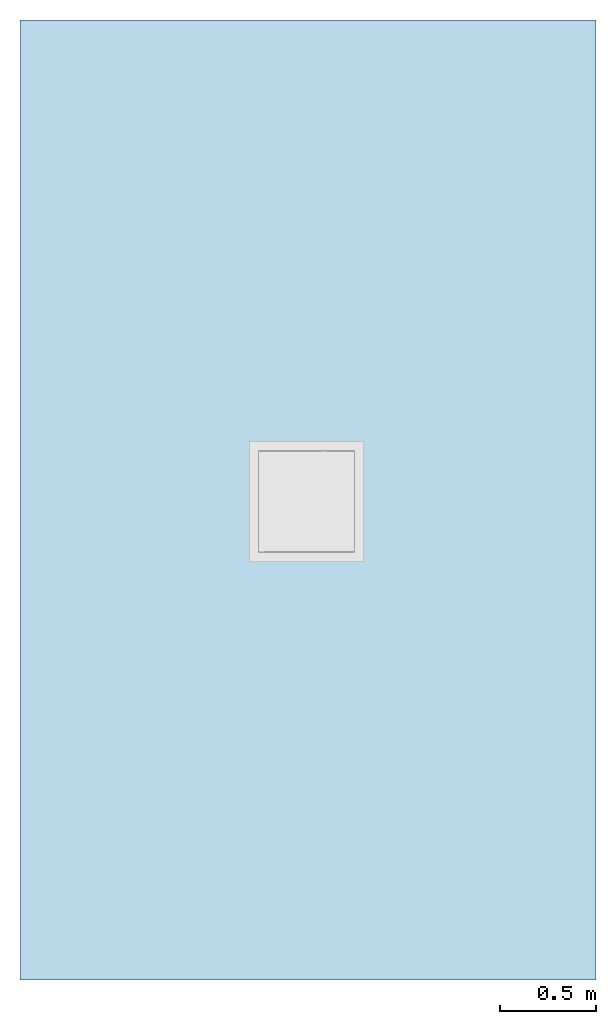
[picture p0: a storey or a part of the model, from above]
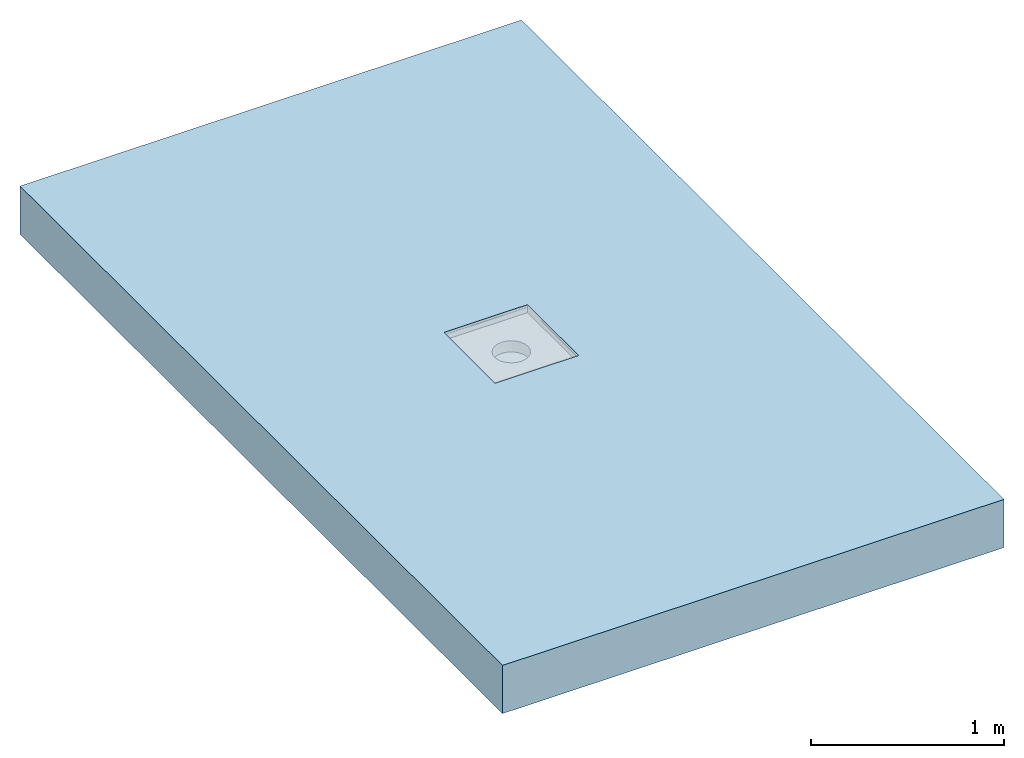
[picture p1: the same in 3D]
Properties of the parts of a building model (IFC2X3)

# File
Description: ViewDefinition [CoordinationView]
File name: Project Number
Time: 2016-11-22T10:02:17
Written by: The EXPRESS Data Manager Version 5.01.0100.02.64mod : 6 Jun 2012
Made in: 20130308_1515(x64) - Exporter 2014.0.2013.0308 - Default UI
Comment: STEP Physical File produced by: The EXPRESS Data Manager Version 5.01.0100.02.64mod : 6 Jun 2012 * Module: EDMstepFileFactory/EDMstandAlone * Creation date: Tue Nov 22 10:02:17 2016 * Host: IN-BLR-PC-0012 * Database: C:\Users\pakumar\AppData\Local\Temp\{4FF520C0-FC0E-452F-8ADC-81A6F5B29089}\ifc * Database version: 5507 * Database creation date: Tue Nov 22 10:02:16 2016 * Schema: IFC2X3 * Model: DataRepository.ifc * Model creation date: Tue Nov 22 10:02:16 2016 * Header model: DataRepository.ifc_HeaderModel * Header model creation date: Tue Nov 22 10:02:16 2016 * EDMuser: sdai-user * EDMgroup: sdai-group * License ID and type: 5605 : Permanent license. Expiry date: * EDMstepFileFactory options: 020000

# IfcProject, Project Number
LongName: Project Name; Phase: Project Status

# IfcSite, Default
RefLatitude: 42, 21, 30, 344238; RefLongitude: -71, -3, -35, -194702; RefElevation: 0 mm

# IfcBuilding
Pset_BuildingCommon - NumberOfStoreys: 1
Other - Project Name: Project Name; Project Issue Date: Issue Date; Client Name: Owner; Project Number: Project Number; Project Address: Enter address here; Project Status: Project Status

# IfcBuildingStorey, Level 1
LongName: Level 1; Elevation: 0 mm
Constraints - Elevation Base: Project Base Point; Elevation: 0 mm
Graphics - Line Weight: 1; Line Pattern: Grid Line 1/2"; Color: 0; Symbol at End 1 Default: no; Symbol at End 2 Default: yes; Symbol: Level Head - Circle: Level Head - Circle
Identity Data - Building Story: yes; Name: Level 1; Structural: no
Dimensions - Computation Height: 0 mm

# IfcFlowTerminal: 416753 - Hygienic Extended Channel - with Gully 218 - 500mm LG - 500mm Wide, ACO Tray Channel - Hygienic - Extended - 500mm Wide:416753 - Hygienic Extended Channel - with Gully 218 - 500mm LG - 500mm Wide:439377
In: Level 1
Material: Stainless Steel AISI 304, Stainless Steel AISI 304 - Grating
Construction - Detail - Outlet 142mm: no; Grating: yes; Detail - Outlet 200: yes; 416874 - 468 x 398mm - Mesh Grating - L15 - Stainless Steel 1.4301: no; 416828 - 468 x 499mm - Ladder Grating - R50 - Stainless Steel 1.4301: no; 416832 - 468 x 499mm - Ladder Grating - M125 - Stainless Steel 1.4301: no; 416834 - 468 x 398mm - Ladder Grating - M125 - Stainless Steel 1.4301: no; 416830 - 468 x 398mm - Ladder Grating - R50 - Stainless Steel 1.4301: no; 416892 - 468 x 499mm - Mesh Grating - L15 - Stainless Steel 1.4301: no; 416872 - 468 x 499mm - Mesh Grating - L15 - Stainless Steel 1.4301: yes; 416894 - 468 x 398mm - Mesh Grating - L15 - Stainless Steel 1.4301: no
Phasing - Phase Created: New Construction
Mechanical - System Classification: Sanitary
Identity Data - Mark: 30; Manufacturer: ACO Building Drainage; Watermark2: This file is water marked and users are prohibited to reproduce, adapt, distribute this information.; E-mail Sales: abdcommercial@aco.co.uk; Fax: +44 (0)1462 851490; Watermarked By: www.acobd.com; E-mail Technical: abdtechnical@aco.co.uk; Watermark1: This file is the property of ACO Technologies PLC.; Watermarked With: BIM Manager Premium Suite.; Cost: 0; Address: ACO Business Centre, Caxton Road, Bedford, MK41 0LF; Website: www.acobd.com; Telephone: +44 (0)1462 816666
Constraints - Level: Level: Level 1
Pset_ManufacturerTypeInformation - Manufacturer: ACO Building Drainage
General - Product Type: Extended Kitchen Tray Channel; Channel Colour: passivated stainless steel surface ( matt grey); Foul air trap seal Colour: Black; Product Range: ACO Hygiene First; Price: POA - contact ACO; Installation guidelines: http://issuu.com/acobuildingdrainage/docs/aco_hygiene_first_catalogue/17?e=0; Weight (Kg): 7.2; Maintenance guidelines: http://issuu.com/acobuildingdrainage/docs/aco_hygiene_first_catalogue/17?e=0; Outlet Diameter (mm): 200; Product Standard: EN 1253 / EN 1672 / EN ISO 14159; Foul air trap Recyclable: Fully recyclable; Channel Dimension: 500 x 530; Channel Material: Stainless steel 1.4301 (EN 10088); Channel Recycled material content: 20 - 30 %; Product Code: 416753; Foul air trap Recycled material content: 0%; Load Class: A15 - C250 (EN 1253); Channel Recyclable: Fully recyclable; Foul air trap seal Material: NBR; Product Description: ACO Hygiene First Extended Kitchen Tray Channel 500 x 530 / 200 Dia Outlet & Foul Air Trap
Model Properties - Grating Product Code 416874: N/A; Grating Product Code 416894: N/A; Grating Product Code 416832: Load Class M 125 (EN 1253) - Ladder Grate - Stainless steel 1.4301 (EN 10088) - 468 x 499 - 17kg; Grating Product Code 416830: N/A; Grating Product Code 416892: Load Class L 15 (EN 1253) - Mesh Grate - Stainless steel 1.4301 (EN 10088) - 468 x 499 - 6.4kg; Grating Product Code 416872: Load Class L 15 (EN 1253) - Mesh Grate - Stainless steel 1.4301 (EN 10088) - 468 x 499 - 6.2kg; Grating Product Code 416828: Load Class R 50 (EN 1253) - Ladder Grate - Stainless steel 1.4301 (EN 10088) - 468 x 499 - 12.5kg; Grating Product Code 416834: N/A
Dimensions - End Plate: 500 mm; Grating Height: 21 mm; Grating Length: 298 mm; Inside Outlet Rad: 98 mm; Endplate Position: 500 mm; Outlet: 200 mm; End Connection Plate End: -500 mm; Floor Cut Void Height: 62.8 mm; Length Channel: -470 mm; Grating Void Cut Length: 500 mm; Outside Outlet Rad: 100 mm; x: -515 mm; Invert Depth: 50 mm; Spigot Distance: 250 mm; End Connection Plate Start: -470 mm; Number of gratings: 1; Depth: 29 mm
Other - Hygienic Standard Channel - 1000mm LG - 500mm Wide: no; Hygienic Standard Channel - 800mm LG - 500mm Wide: no; Flow: 0.155385 m3/s; Spigot Outlets Channels: yes; Hygienic Standard Channel - 500mm LG - 500mm Wide: yes; Invert Depth Detail: 51.5 mm; Number mesh: 10

# IfcOpeningElement: Recess
In: Level 1
Dimensions - Perimeter: 16000 mm; Volume: 160.907 ft3; Thickness: 304.8 mm; Area: 161.459 ft2
Constraints - Related to Mass: no; Level: Level: Level 1; Height Offset From Level: 0 mm; Room Bounding: yes
Phasing - Phase Created: New Construction
Structural - Structural: no; Enable Analytical Model: no
Analytical Properties - Absorptance: 0.7; Roughness: 3
Identity Data - Assembly Description: Floor Construction; Assembly Code: B1010
Graphics - Coarse Scale Fill Color: 0
Construction - Function: Interior; Default Thickness: 304.8 mm

# IfcSlab: Floor:Generic - 12", Floor:Generic - 12":184145
In: Level 1
PredefinedType: FLOOR; Material: Default Floor 304.8 mm
Dimensions - Perimeter: 16000 mm; Volume: 160.907 ft3; Thickness: 304.8 mm; Area: 161.459 ft2
Constraints - Related to Mass: no; Level: Level: Level 1; Height Offset From Level: 0 mm; Room Bounding: yes
Phasing - Phase Created: New Construction
Structural - Structural: no; Enable Analytical Model: no
Pset_SlabCommon - Reference: Generic - 12"; IsExternal: no; LoadBearing: yes
Analytical Properties - Absorptance: 0.7; Roughness: 3
Identity Data - Assembly Description: Floor Construction; Assembly Code: B1010
Graphics - Coarse Scale Fill Color: 0
Construction - Function: Interior; Default Thickness: 304.8 mm
